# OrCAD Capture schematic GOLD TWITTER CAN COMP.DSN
size A4; title: GTWICAN

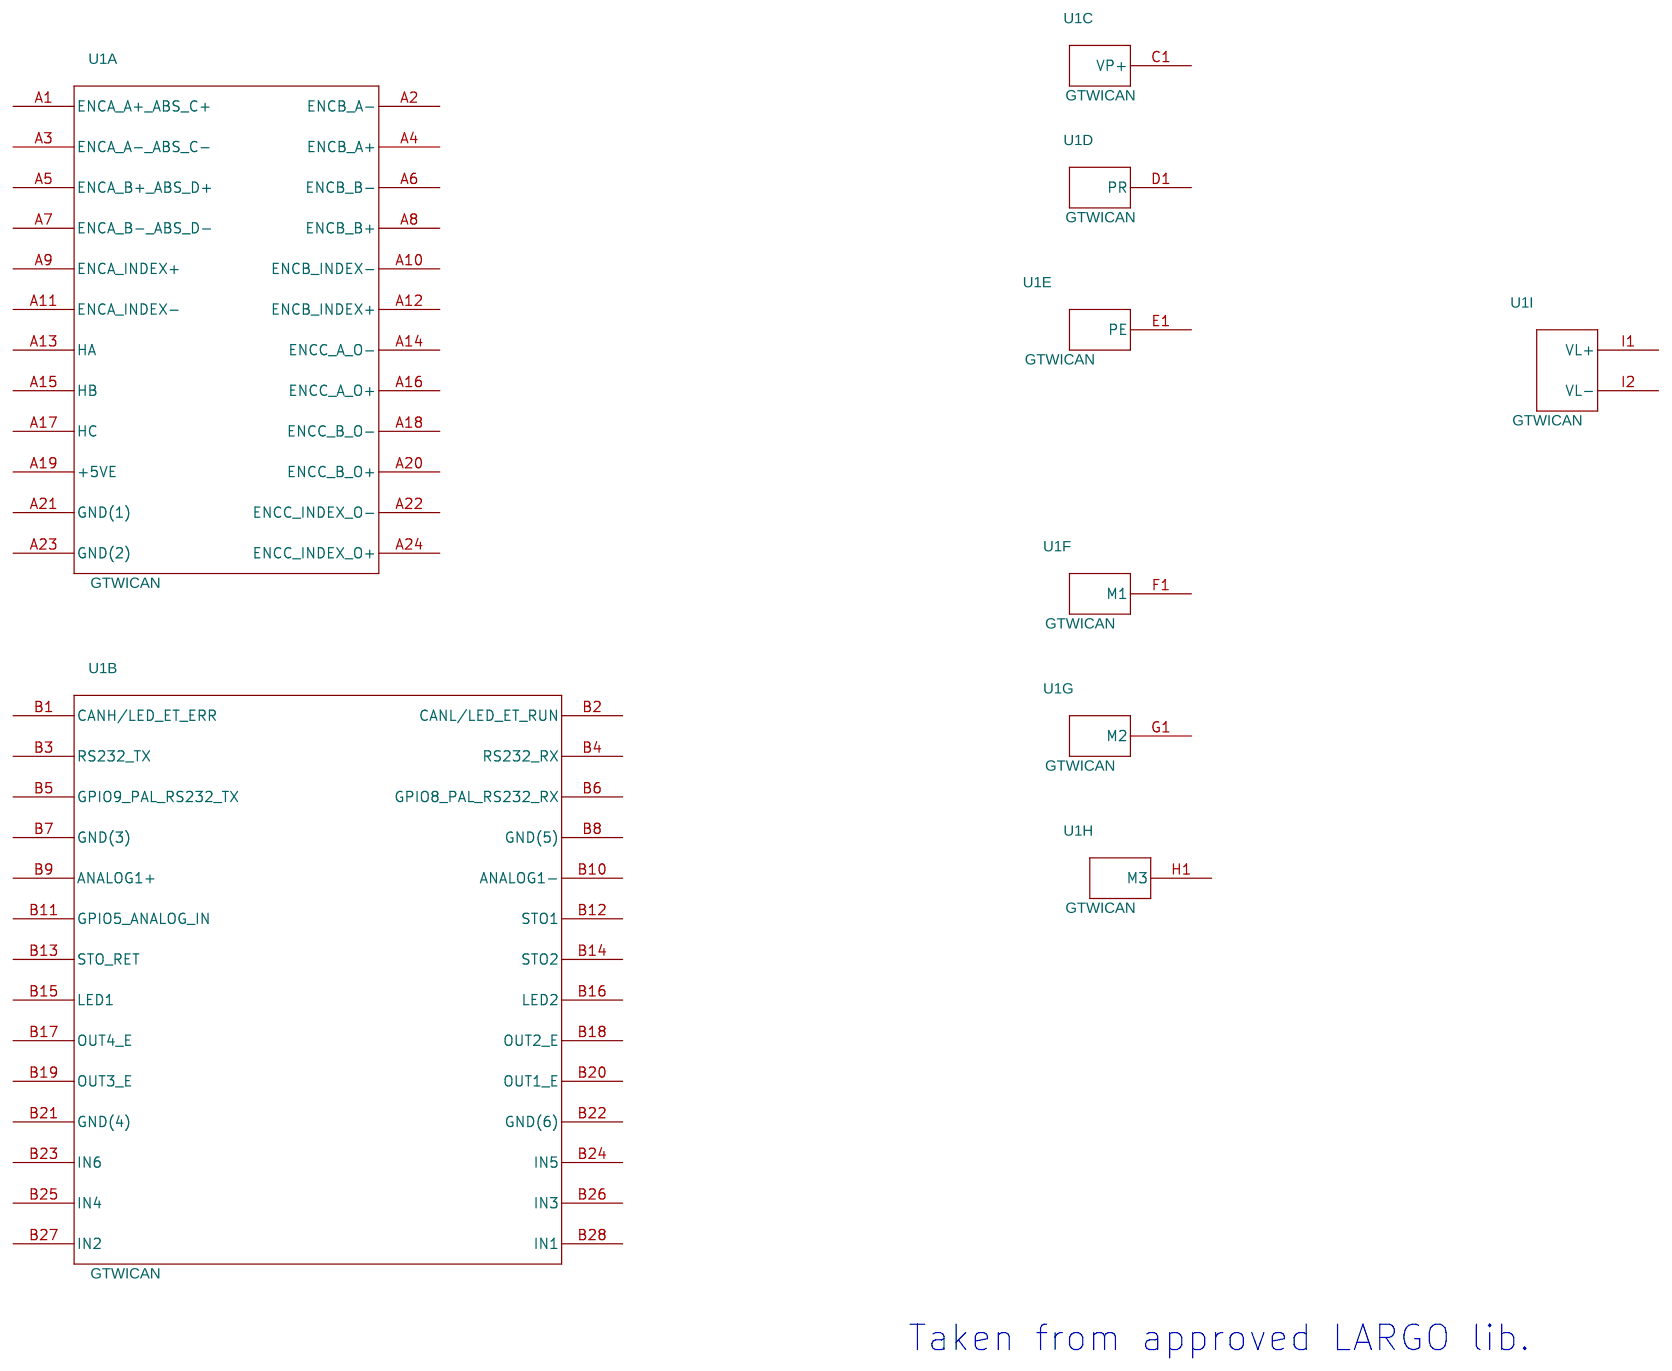
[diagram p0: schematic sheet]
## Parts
U1  GTWICAN  [NANO_V1]  (sections A,B,C,D,E,F,G,H,I)

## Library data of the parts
U1 = GTWICAN_GTWICAN

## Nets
+5VE: U1.A19(+5VE)
GND(1): U1.A21(GND(1))
GND(2): U1.A23(GND(2))
GND(3): U1.B7(GND(3))
GND(4): U1.B21(GND(4))
GND(5): U1.B8(GND(5))
GND(6): U1.B22(GND(6))
PE: U1.E1(PE)
PR: U1.D1(PR)
VL+: U1.I1(VL+)
VL-: U1.I2(VL-)
VP+: U1.C1(VP+)

Not connected (* = marked no-connect by the designer): U1 A1(ENCA_A+_ABS_C+) A2(ENCB_A-) A3(ENCA_A-_ABS_C-) A4(ENCB_A+) A5(ENCA_B+_ABS_D+) A6(ENCB_B-) A7(ENCA_B-_ABS_D-) A8(ENCB_B+) A9(ENCA_INDEX+) A10(ENCB_INDEX-) A11(ENCA_INDEX-) A12(ENCB_INDEX+) A13(HA) A14(ENCC_A_O-) A15(HB) A16(ENCC_A_O+) A17(HC) A18(ENCC_B_O-) A20(ENCC_B_O+) A22(ENCC_INDEX_O-) A24(ENCC_INDEX_O+) B1(CANH/LED_ET_ERR) B2(CANL/LED_ET_RUN) B3(RS232_TX) B4(RS232_RX) B5(GPIO9_PAL_RS232_TX) B6(GPIO8_PAL_RS232_RX) B9(ANALOG1+) B10(ANALOG1-) B11(GPIO5_ANALOG_IN) B12(STO1) B13(STO_RET) B14(STO2) B15(LED1) B16(LED2) B17(OUT4_E) B18(OUT2_E) B19(OUT3_E) B20(OUT1_E) B23(IN6) B24(IN5) B25(IN4) B26(IN3) B27(IN2) B28(IN1) F1(M1) G1(M2) H1(M3)

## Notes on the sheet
- Taken from approved LARGO lib.
